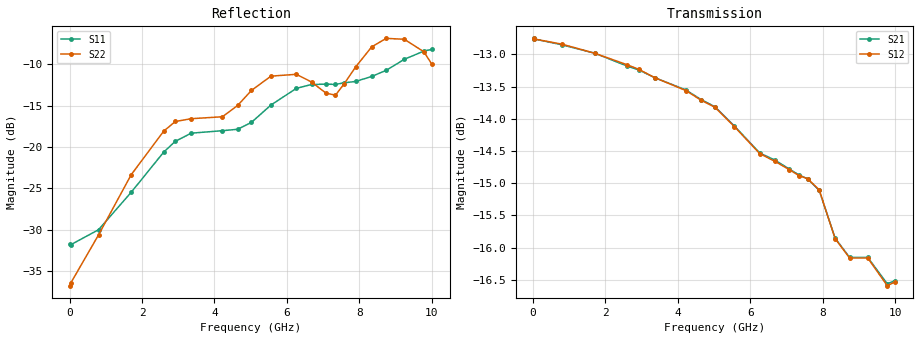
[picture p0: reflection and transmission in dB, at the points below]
! Integrated Device Technology
! Corporate Headquarters
! 6024 Silver Creek Valley Road
! San Jose, CA 95138  USA
! Phone:  1-408-284-8200
! Toll Free:  1-800-223-1366
! Webpage:  http://www.idt.com/
! Timing and RF Division
! 515 Groton Road, Suite 102
! Westford, MA 01886-6024
! Device:  F1958
! Description: 7-bit 0.25 dB Digital Step Attenuator
! Frequency:  0.001 -  6.000 GHz
! Package:  4x4 mm Thin QFN Plastic Package: 24 pin
! Ports:  2 RF, 12 DC
!  Pin  1  = D0
!  Pin  2  = VDD
!  Pin  3  = VMODE
!  Pin  4  = GND
!  Pin  5  = RF1  =  Port 1
!  Pin  6  = GND
!  Pin  7  = GND
!  Pin  8  = GND
!  Pin  9  = GND
!  Pin 10  = GND
!  Pin 11  = GND
!  Pin 12  = GND
!  Pin 13  = GND
!  Pin 14  = RF2  =  Port 2
!  Pin 15  = GND
!  Pin 16  = LE
!  Pin 17  = CLK
!  Pin 18  = DATA
!  Pin 19  = D6
!  Pin 20  = D5
!  Pin 21  = D4
!  Pin 22  = D3
!  Pin 23  = D2
!  Pin 24  = D1
! State:  47
! Atten State:  11.75 dB
! Voltage:  +3.30 Volts
! Current:  0.258 mA
! Data:  The device was measured on a F1958 evaluation board which has
!  individual transmission lines to the RF pins.  Data was collected
!  using a calibrated network analyzer.  The evaluation board was
!  de-embedded using Automatic Fixture Removal (AFR).
!  The reference plane is the edge of the package pin.
! Misc:
!  Action Tracker AT0419
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# GHz S dB R 50
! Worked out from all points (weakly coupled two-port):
!   500 points, 20 MHz to 10 GHz, reference 50 ohm
!   highest |S21| = -12.75 dB at 20 MHz (marker M1); lowest = -16.6 dB at 9.78 GHz (marker M2)
!   lowest |S11| = -31.8 dB at 40 MHz (marker M3), VSWR 1.05, Z = 47.5 - j0.0669 ohm
!   |S11| at or under -10 dB: start of sweep to 9.03 GHz
!   |S22| runs from -36.8 to -6.7 dB; largest |S21 - S12| = 0.00067
!   S11 on the Smith chart (normalised r, x): 20 MHz: 0.95, -0.00; 6.26 GHz: 0.66, +0.16; 10 GHz: 0.67, +0.60
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0.02  -31.76 -178.3  -12.75 -0.5  -12.75 -0.5  -36.75 -173.3
0.04  -31.79 -178.4  -12.76 -0.9  -12.76 -0.9  -36.38 -170.5
0.8  -29.99 175.3  -12.85 -15.2  -12.84 -15.2  -30.62 -160.2
1.7  -25.48 175.9  -12.98 -32.0  -12.98 -31.9  -23.36 -168.6
2.6  -20.61 -178.6  -13.18 -48.7  -13.16 -48.7  -18.08 -174.4
2.92  -19.31 -175.5  -13.24 -54.6  -13.23 -54.7  -16.92 -175.0
3.36  -18.33 -172.7  -13.36 -62.8  -13.36 -62.9  -16.58 -176.6
4.22  -18.03 -175.9  -13.55 -78.6  -13.56 -78.7  -16.35 156.3
4.64  -17.86 174.5  -13.70 -86.3  -13.71 -86.4  -14.98 140.8
5.02  -17.03 163.4  -13.81 -93.5  -13.82 -93.5  -13.17 130.9
5.56  -14.93 152.4  -14.11 -103.4  -14.12 -103.4  -11.44 128.4
6.26  -12.92 148.7  -14.53 -115.6  -14.54 -115.6  -11.22 132.0
6.68  -12.45 146.7  -14.64 -123.0  -14.66 -122.9  -12.15 127.5
7.08  -12.41 143.4  -14.78 -131.1  -14.79 -131.0  -13.50 110.0
7.34  -12.44 140.9  -14.87 -135.6  -14.88 -135.5  -13.74 90.9
7.58  -12.25 137.0  -14.93 -139.9  -14.93 -139.8  -12.37 75.9
7.9  -12.08 129.3  -15.11 -147.0  -15.10 -147.1  -10.31 66.7
8.34  -11.48 119.8  -15.85 -154.7  -15.86 -154.8  -7.91 63.6
8.74  -10.74 112.9  -16.15 -157.8  -16.16 -157.7  -6.88 67.2
9.24  -9.41 104.2  -16.15 -166.4  -16.16 -166.5  -6.99 76.0
9.78  -8.42 99.7  -16.56 -173.2  -16.59 -173.2  -8.50 78.1
10  -8.21 99.2  -16.51 -176.2  -16.53 -176.1  -10.00 73.4
